VERSION 5.8 ;
BUSBITCHARS "[]" ;
DIVIDERCHAR "/" ;
UNITS
  DATABASE MICRONS 1000 ;
END UNITS
MANUFACTURINGGRID 0.005 ;

# Synthetic stack for the EOL-enclosure pre-screen tests. Every name and value is invented.
# V1 states three checked rules (class VB SHORTEDGEONLY on both metals, class VA on the metal
# above, class VA with an exact overhang on the metal below) and one form that is not checked
# (MINEOLWIDTH); V2 names a cut class it does not define.

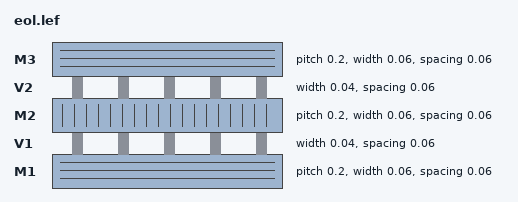
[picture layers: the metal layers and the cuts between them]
LAYER M1
  TYPE ROUTING ;
  DIRECTION HORIZONTAL ;
  PITCH 0.2 ;
  WIDTH 0.06 ;
  SPACING 0.06 ;
END M1

LAYER V1
  TYPE CUT ;
  WIDTH 0.04 ;
  SPACING 0.06 ;
  PROPERTY LEF58_CUTCLASS "CUTCLASS VA WIDTH 0.04 ; CUTCLASS VB WIDTH 0.04 LENGTH 0.08 ;" ;
  PROPERTY LEF58_EOLENCLOSURE "
    EOLENCLOSURE 0.1 CUTCLASS VB SHORTEDGEONLY 0.02 ;
    EOLENCLOSURE 0.1 CUTCLASS VA ABOVE 0.03 ;
    EOLENCLOSURE 0.07 CUTCLASS VA BELOW 0.02 0.0 ;
    EOLENCLOSURE 0.1 MINEOLWIDTH 0.05 CUTCLASS VB SHORTEDGEONLY 0.02 ; " ;
END V1

LAYER M2
  TYPE ROUTING ;
  DIRECTION VERTICAL ;
  PITCH 0.2 ;
  WIDTH 0.06 ;
  SPACING 0.06 ;
END M2

LAYER V2
  TYPE CUT ;
  WIDTH 0.04 ;
  SPACING 0.06 ;
  PROPERTY LEF58_EOLENCLOSURE "EOLENCLOSURE 0.1 CUTCLASS VC 0.02 ;" ;
END V2

LAYER M3
  TYPE ROUTING ;
  DIRECTION HORIZONTAL ;
  PITCH 0.2 ;
  WIDTH 0.06 ;
  SPACING 0.06 ;
END M3

VIA VA12 DEFAULT
  LAYER M1 ;
    RECT -0.02 -0.02 0.02 0.02 ;
  LAYER V1 ;
    RECT -0.02 -0.02 0.02 0.02 ;
  LAYER M2 ;
    RECT -0.02 -0.02 0.02 0.02 ;
END VA12

VIA VAW DEFAULT
  LAYER M1 ;
    RECT -0.06 -0.04 0.03 0.04 ;
  LAYER V1 ;
    RECT -0.02 -0.02 0.02 0.02 ;
  LAYER M2 ;
    RECT -0.02 -0.02 0.02 0.02 ;
END VAW

VIA VAOUT DEFAULT
  LAYER M1 ;
    RECT -0.02 -0.02 0.02 0.02 ;
  LAYER V1 ;
    RECT -0.02 -0.02 0.02 0.02 ;
  LAYER M2 ;
    RECT -0.02 -0.02 0.0 0.02 ;
END VAOUT

VIA VB12 DEFAULT
  LAYER M1 ;
    RECT -0.03 -0.07 0.03 0.07 ;
  LAYER V1 ;
    RECT -0.02 -0.04 0.02 0.04 ;
  LAYER M2 ;
    RECT -0.02 -0.04 0.02 0.04 ;
END VB12

VIA VB12P DEFAULT
  LAYER M1 ;
    RECT -0.03 -0.07 0.03 0.07 ;
  LAYER V1 ;
    RECT -0.02 -0.04 0.02 0.04 ;
  LAYER M2 ;
    RECT -0.03 -0.045 0.03 0.045 ;
END VB12P

END LIBRARY
